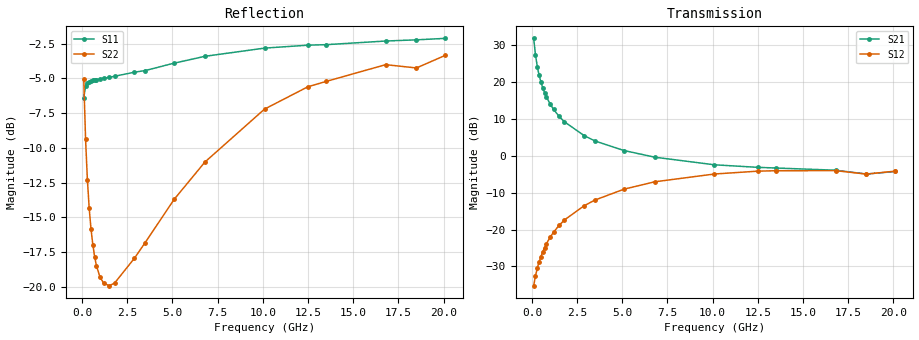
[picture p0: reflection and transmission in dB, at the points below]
!  Infineon Technologies AG
! BFR380L3 , PF131585-7, No.6, Th 09.10.01, soldered on pcb-board, measured with PP GSG850
!  Vce=3.0 V,  Ic=75.0 mA
! Common Emitter S-Parameters:  15. November 2001
#  GHz  S  MA  R  50
! f  S11  S21  S12  S22
! GHz  Mag  Ang  Mag  Ang  Mag  Ang  Mag  Ang
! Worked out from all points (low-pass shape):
!   201 points, 100 MHz to 20.1 GHz, reference 50 ohm
!   highest |S21| = 31.88 dB at 100 MHz (marker M1); lowest = -4.9 dB at 18.5 GHz (marker M2)
!   |S21| within 3 dB of the highest: start of sweep to 166.6 MHz
!   lowest |S11| = -6.4 dB at 100 MHz (marker M3), VSWR 2.84, Z = 23.9 - j27.4 ohm
!   |S11| at or under -10 dB: nowhere
!   |S22| runs from -19.9 to -3.3 dB; largest |S21 - S12| = 39
!   S11 on the Smith chart (normalised r, x): 100 MHz: 0.48, -0.55; 500 MHz: 0.29, -0.07; 2.9 GHz: 0.28, +0.31; 6.8 GHz: 0.33, +0.80; 12.5 GHz: 0.53, +1.53; 20.1 GHz: 1.05, +2.59
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0.1  0.4796 -113.2  39.25 127.9  0.01735 56.4  0.5572 -53.0
0.2  0.5264 -144.7  23.36 109.3  0.0236 58.1  0.3392 -72.8
0.3  0.5391 -158.0  16.26 101.0  0.03006 61.1  0.2428 -82.4
0.4  0.5469 -165.7  12.41 95.8  0.03639 64.3  0.1918 -88.9
0.5  0.5503 -170.9  10 92.0  0.0431 66.5  0.1614 -94.1
0.6  0.5529 -174.8  8.386 89.0  0.05007 68.1  0.1419 -98.3
0.7  0.5557 -178.3  7.221 86.4  0.05694 69.2  0.1285 -102.1
0.8  0.5562 179.0  6.335 84.0  0.06398 69.8  0.1192 -105.5
1  0.5594 174.1  5.103 79.9  0.0782 70.4  0.1082 -111.5
1.2  0.5638 170.1  4.274 76.2  0.0923 70.3  0.1031 -116.9
1.5  0.5669 164.5  3.45 71.0  0.1137 69.7  0.1009 -123.7
1.8  0.5723 159.5  2.898 66.2  0.1351 68.5  0.103 -129.8
2.9  0.5918 143.1  1.876 50.4  0.2114 62.2  0.1266 -149.0
3.5  0.6002 135.0  1.59 42.6  0.2523 58.1  0.1443 -156.3
5.1  0.638 116.3  1.181 24.9  0.3537 46.4  0.2064 -178.8
6.8  0.6752 99.2  0.9596 10.4  0.4452 34.2  0.2811 159.2
10.1  0.7227 74.8  0.7567 -8.7  0.5677 11.5  0.436 126.5
12.5  0.7405 62.0  0.699 -19.2  0.6205 -3.7  0.5247 105.4
13.5  0.7436 57.7  0.6847 -22.9  0.629 -9.7  0.5482 98.3
16.8  0.7664 46.1  0.6391 -33.7  0.6305 -25.7  0.6301 77.0
18.5  0.774 44.3  0.5673 -41.2  0.5661 -34.0  0.6131 71.5
20.1  0.7835 37.2  0.614 -44.3  0.6208 -39.3  0.6807 60.7
